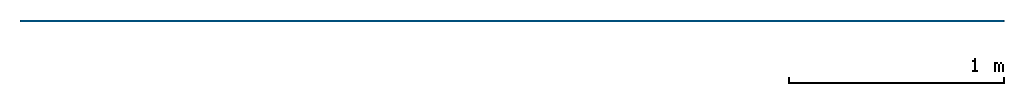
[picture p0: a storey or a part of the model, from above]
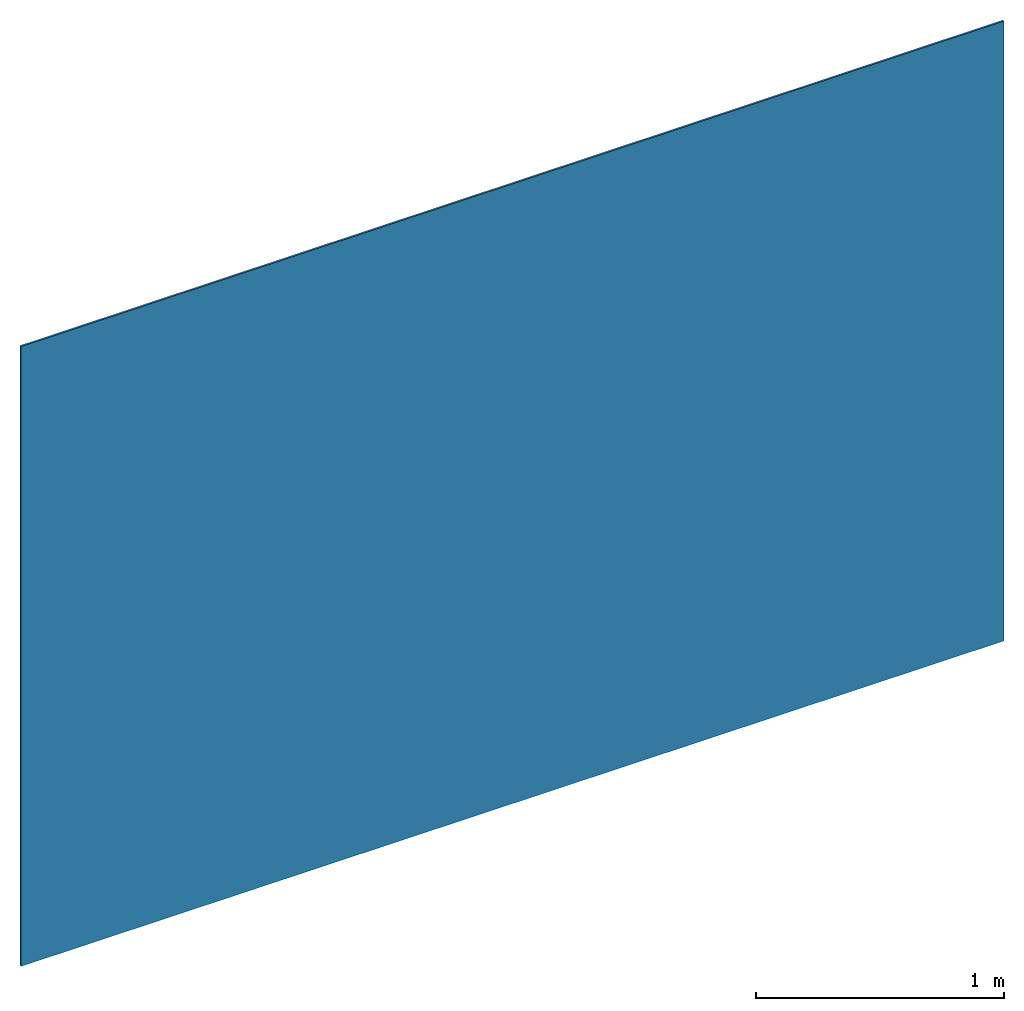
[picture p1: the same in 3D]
Properties of the parts of a building model (IFC4)

# File
Description: IFC4 Wall Geometric Model
File name: wall_model.ifc
Time: 2026-06-25T12:00:00
Author: AI Assistant
Organization: Architecture Corp
Written by: Processor
Made in: AI Generator
Comment: 1. Project and Spatial Structure
Comment: 2. Spatial Aggregation
Comment: 3. Global Units and Contexts
Comment: 4. Wall Product Definition
Comment: 5. Wall Placement and Local Coordinate System
Comment: 6. Wall Geometry (Swept Solid Extrusion)
Comment: Profile Definition (Arbitrary Closed Profile for Thickness & Length)
Comment: Length = 4.572m (15ft), Thickness = 0.009m (9mm)
Comment: Extrusion Direction and Height = 3.048m (10ft)

# IfcProject, Project Wall 15x10
Description: Example Wall Project

# IfcSite, Site
Description: Project Site

# IfcBuilding, Building
Description: Project Building

# IfcBuildingStorey, Ground Floor
Description: Level 0; Elevation: 0 m

# IfcWall, Standard Wall
In: Ground Floor
Description: Wall 15ft x 10ft x 9mm
